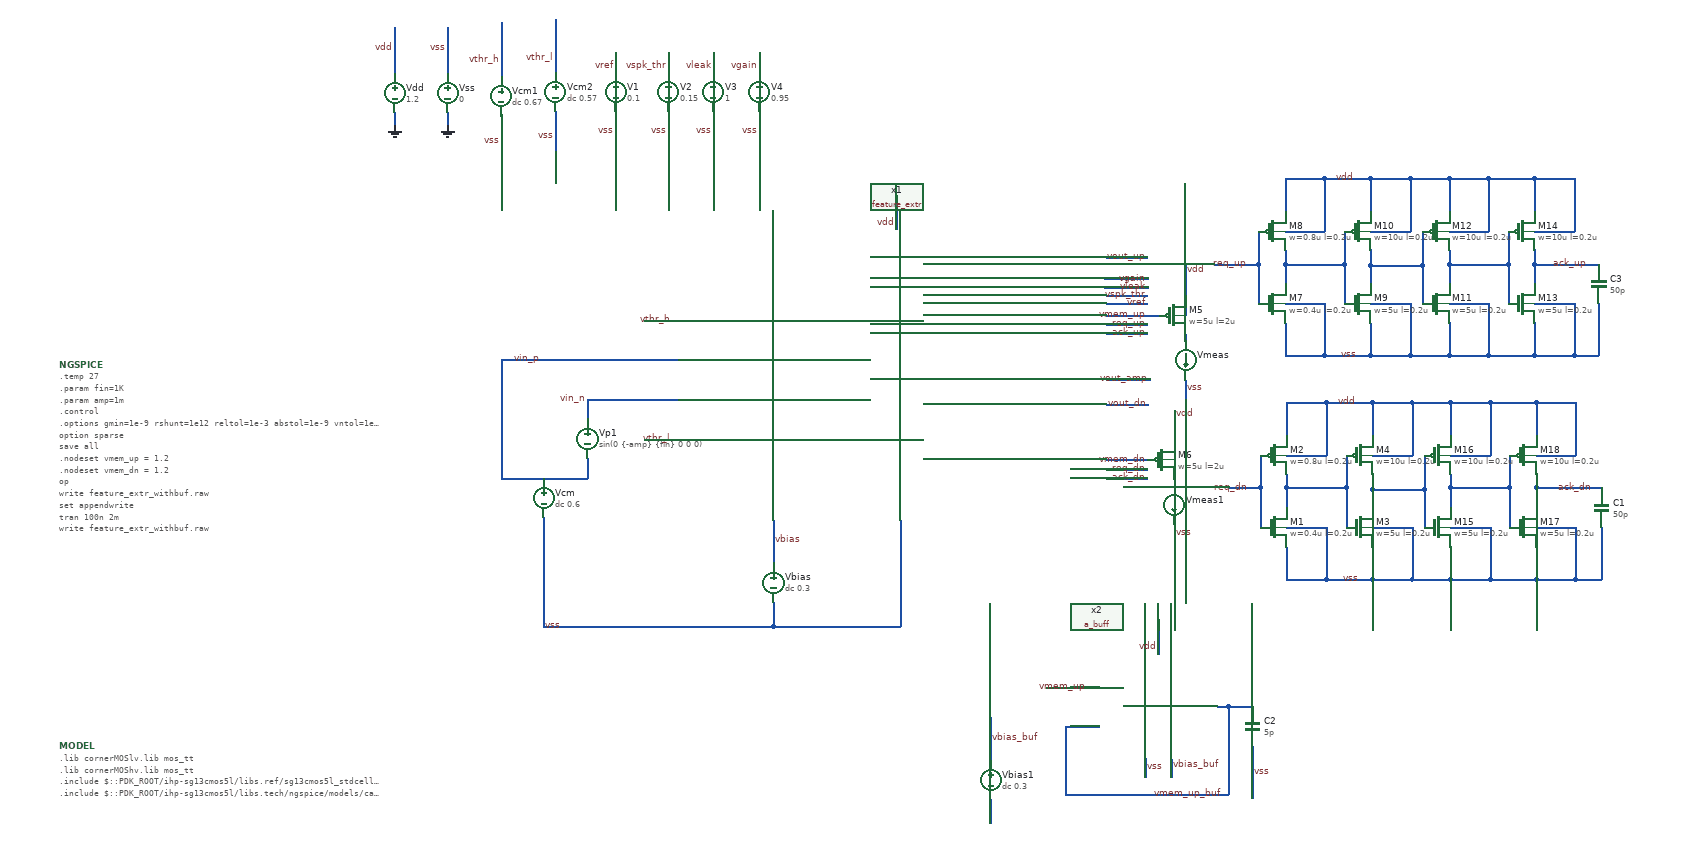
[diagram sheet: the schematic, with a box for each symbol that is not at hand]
v {xschem version=3.4.8RC file_version=1.3}
G {}
K {}
V {}
S {}
F {}
E {}
B 2 2471.25 -692.5 3271.25 -292.5 {flags=graph
y1=0.53
y2=0.74
ypos1=0
ypos2=2
divy=5
subdivy=1
unity=1
x1=0.0013195036
x2=0.0013233667
divx=5
subdivx=1
xlabmag=1.0
ylabmag=1.0
node="vout_amp
vthr_h
vthr_l
vthr
vint"
dataset=-1
unitx=1
logx=0
logy=0
rawfile=$netlist_dir/feature_extr.raw
sim_type=tran
autoload=1
color="3 7 4 12 9"}
B 2 3291.25 -1107.5 4091.25 -707.5 {flags=graph
y1=0.0013
y2=0.22
ypos1=0
ypos2=2
divy=5
subdivy=1
unity=1
x1=0.0013195036
x2=0.0013233667
divx=5
subdivx=1
xlabmag=1.0
ylabmag=1.0
node="vout_up
vout_dn"
dataset=-1
unitx=1
logx=0
logy=0
rawfile=$netlist_dir/feature_extr.raw
sim_type=tran
autoload=1
color="4 5"
hilight_wave=1}
B 2 3291.25 -692.5 4091.25 -292.5 {flags=graph
y1=1e-10
y2=2.5e-06
ypos1=0
ypos2=2
divy=5
subdivy=1
unity=1
x1=0.0013195036
x2=0.0013233667
divx=5
subdivx=1
xlabmag=1.0
ylabmag=1.0
dataset=-1
unitx=1
logx=0
logy=0
sim_type=tran
autoload=1
color="5 4"
node="i(v.x1.vmeas3)
i(v.x1.vmeas1)"
hilight_wave=1}
B 2 2481.25 -222.5 3281.25 177.5 {flags=graph
y1=0.53
y2=0.98
ypos1=0
ypos2=2
divy=5
subdivy=1
unity=1
x1=0.0013195036
x2=0.0013233667
divx=5
subdivx=1
xlabmag=1.0
ylabmag=1.0
dataset=-1
unitx=1
logx=0
logy=0
rawfile=$netlist_dir/feature_extr.raw
sim_type=tran
autoload=1
color="10 7 12"
node="vout_amp
x1.net6
x1.net5"}
B 2 3303.125 -267.5 4103.125 132.5 {flags=graph
y1=1.1e-09
y2=4.7e-08
ypos1=0
ypos2=2
divy=5
subdivy=1
unity=1
x1=0.0013195036
x2=0.0013233667
divx=5
subdivx=1
xlabmag=1.0
ylabmag=1.0
dataset=-1
unitx=1
logx=0
logy=0
sim_type=tran
autoload=1
color="4 6"
node="i(v.x1.vmeas4)
i(v.x1.vmeas2)"
hilight_wave=-1}
B 2 3330 196.25 4130 596.25 {flags=graph
y1=2.2e-09
y2=6.8e-08
ypos1=0
ypos2=2
divy=5
subdivy=1
unity=1
x1=0.0013195036
x2=0.0013233667
divx=5
subdivx=1
xlabmag=1.0
ylabmag=1.0
node=i(vmeas)
dataset=-1
unitx=1
logx=0
logy=0
rawfile=$netlist_dir/feature_extr.raw
sim_type=tran
autoload=1
color=4
hilight_wave=-1}
B 2 4170 196.25 4970 596.25 {flags=graph
y1=2.1e-09
y2=3.5e-08
ypos1=0
ypos2=2
divy=5
subdivy=1
unity=1
x1=0.0013195036
x2=0.0013233667
divx=5
subdivx=1
xlabmag=1.0
ylabmag=1.0
dataset=-1
unitx=1
logx=0
logy=0
rawfile=$netlist_dir/feature_extr.raw
sim_type=tran
autoload=1
color=4
node=i(vmeas1)
hilight_wave=-1}
B 2 4108.525390625 -695.302734375 4908.525390625 -295.302734375 {flags=graph
y1=-0.004
y2=1.3
ypos1=0
ypos2=2
divy=5
subdivy=1
unity=1
x1=0.0013195036
x2=0.0013233667
divx=5
subdivx=1
xlabmag=1.0
ylabmag=1.0
node="req_up
ack_up"
dataset=-1
unitx=1
logx=0
logy=0
rawfile=$netlist_dir/feature_extr.raw
sim_type=tran
autoload=1
color="5 4"
hcursor2_y=-0.86477319
hilight_wave=0}
B 2 2471.25 -1107.5 3271.25 -707.5 {flags=graph
y1=0.59
y2=0.61
ypos1=0
ypos2=2
divy=5
subdivy=1
unity=1
x1=0.0013195036
x2=0.0013233667
divx=5
subdivx=1
xlabmag=1.0
ylabmag=1.0
node="vin_p
vin_n"
dataset=-1
unitx=1
logx=0
logy=0
rawfile=$netlist_dir/feature_extr.raw
sim_type=tran
autoload=1
color="6 3"}
B 2 4108.2275390625 -1108.84765625 4908.2275390625 -708.84765625 {flags=graph
y1=0.94
y2=1.3
ypos1=0
ypos2=2
divy=5
subdivy=1
unity=1
x1=0.0013195036
x2=0.0013233667
divx=5
subdivx=1
xlabmag=1.0
ylabmag=1.0
node="vmem_up
vmem_dn"
dataset=-1
unitx=1
logx=0
logy=0
rawfile=$netlist_dir/feature_extr.raw
sim_type=tran
autoload=1
color="5 4"
hilight_wave=-1}
B 2 4928.2275390625 -1108.84765625 5728.2275390625 -708.84765625 {flags=graph
y1=0.959568
y2=1.558848
ypos1=0
ypos2=2
divy=5
subdivy=1
unity=1
x1=0.0013195036
x2=0.0013233667
divx=5
subdivx=1
xlabmag=1.0
ylabmag=1.0
dataset=-1
unitx=1
logx=0
logy=0
rawfile=$netlist_dir/feature_extr.raw
sim_type=tran
autoload=1
hilight_wave=1
color="5 4"
node="x1.x5.vmem_d
x1.x7.vmem_d"}
B 2 4108.525390625 -265.302734375 4908.525390625 134.697265625 {flags=graph
y1=-0.0036
y2=1.3
ypos1=0
ypos2=2
divy=5
subdivy=1
unity=1
x1=0.0013195036
x2=0.0013233667
divx=5
subdivx=1
xlabmag=1.0
ylabmag=1.0
node="req_dn
ack_dn"
dataset=-1
unitx=1
logx=0
logy=0
rawfile=$netlist_dir/feature_extr.raw
sim_type=tran
autoload=1
color="4 10"
hcursor2_y=-0.86477319
hilight_wave=-1}
B 2 1279.4775390625 14.90234375 2079.4775390625 414.90234375 {flags=graph
y1=0.94
y2=1.3
ypos1=0
ypos2=2
divy=5
subdivy=1
unity=1
x1=0.0013195036
x2=0.0013233667
divx=5
subdivx=1
xlabmag=1.0
ylabmag=1.0
node="vmem_up
vmem_up_buf"
dataset=-1
unitx=1
logx=0
logy=0
sim_type=tran
autoload=1
color="5 4"
hilight_wave=-1
rawfile=$netlist_dir/feature_extr_withbuf.raw}
N 510 -1102.5 510 -1082.5 {
lab=GND}
N 590 -1102.5 590 -1082.5 {
lab=GND}
N 672.5 -727.5 941.25 -727.5 {
lab=vin_p}
N 672.5 -727.5 672.5 -547.5 {lab=vin_p}
N 802.5 -577.5 802.5 -547.5 {lab=vin_p}
N 672.5 -547.5 802.5 -547.5 {lab=vin_p}
N 671.25 -1240 671.25 -1157.5 {lab=vthr_h}
N 671.25 -1100 671.25 -1040 {lab=vss}
N 753.75 -1103.75 753.75 -1043.75 {lab=vss}
N 510 -1232.5 510 -1162.5 {lab=vdd}
N 590 -1232.5 590 -1162.5 {lab=vss}
N 736.25 -487.5 736.25 -322.5 {lab=vss}
N 1277.5 -482.5 1277.5 -322.5 {lab=vss}
N 888.75 -787.5 941.25 -787.5 {lab=vthr_h}
N 888.75 -606.25 941.25 -606.25 {lab=vthr_l}
N 1272.5 -977.5 1272.5 -925 {lab=vdd}
N 1591.25 -882.5 1653.75 -882.5 {lab=vout_up}
N 1591.25 -697.5 1657.5 -697.5 {lab=vout_amp}
N 1591.25 -825 1653.75 -825 {lab=vspk_thr}
N 1591.25 -812.5 1653.75 -812.5 {lab=vref}
N 1591.25 -795 1671.25 -795 {lab=vmem_up}
N 1591.25 -781.25 1653.75 -781.25 {lab=req_up}
N 1591.25 -767.5 1653.75 -767.5 {lab=ack_up}
N 1591.25 -575 1653.75 -575 {lab=vmem_dn}
N 1591.25 -561.25 1653.75 -561.25 {lab=req_dn}
N 1591.25 -547.5 1653.75 -547.5 {lab=ack_dn}
N 2301.25 -733.75 2338.75 -733.75 {lab=vss}
N 2338.75 -812.5 2338.75 -733.75 {lab=vss}
N 1865 -532.5 1865 -502.5 {lab=#net1}
N 1825 -532.5 1825 -472.5 {lab=req_dn}
N 1865 -662.5 1865 -612.5 {lab=vdd}
N 1865 -472.5 1925 -472.5 {lab=vss}
N 1865 -582.5 1925 -582.5 {lab=vdd}
N 1925 -662.5 1925 -582.5 {lab=vdd}
N 1865 -662.5 1925 -662.5 {lab=vdd}
N 1865 -532.5 1955 -532.5 {lab=#net1}
N 1865 -552.5 1865 -532.5 {lab=#net1}
N 1955 -532.5 1955 -472.5 {lab=#net1}
N 1955 -582.5 1955 -532.5 {lab=#net1}
N 1995 -662.5 1995 -612.5 {lab=vdd}
N 1995 -472.5 2055 -472.5 {lab=vss}
N 1995 -582.5 2055 -582.5 {lab=vdd}
N 2055 -662.5 2055 -582.5 {lab=vdd}
N 1995 -662.5 2055 -662.5 {lab=vdd}
N 1925 -662.5 1995 -662.5 {lab=vdd}
N 1777.5 -532.5 1825 -532.5 {lab=req_dn}
N 1825 -582.5 1825 -532.5 {lab=req_dn}
N 2055 -472.5 2055 -393.75 {lab=vss}
N 1865 -442.5 1865 -393.75 {lab=vss}
N 1925 -472.5 1925 -393.75 {lab=vss}
N 1995 -442.5 1995 -393.75 {lab=vss}
N 2303.75 -393.75 2342.5 -393.75 {lab=vss}
N 1865 -393.75 1925 -393.75 {lab=vss}
N 1925 -393.75 1995 -393.75 {lab=vss}
N 1995 -393.75 2055 -393.75 {lab=vss}
N 2342.5 -472.5 2342.5 -393.75 {lab=vss}
N 753.75 -1243.75 753.75 -1163.75 {lab=vthr_l}
N 845.390625 -1194.296875 845.390625 -1164.296875 {lab=vref}
N 845.390625 -1104.296875 845.390625 -1064.296875 {lab=vss}
N 802.5 -667.5 802.5 -637.5 {lab=vin_n}
N 802.5 -667.5 941.25 -667.5 {lab=vin_n}
N 1591.25 -660 1655 -660 {lab=vout_dn}
N 1085 -322.5 1277.5 -322.5 {lab=vss}
N 1085 -483.75 1085 -418.75 {lab=vbias}
N 1085 -358.75 1085 -322.5 {lab=vss}
N 736.25 -322.5 1085 -322.5 {lab=vss}
N 1711.25 -870 1711.25 -795 {lab=vdd}
N 1693.75 -650 1693.75 -575 {lab=vdd}
N 1711.25 -766.25 1711.25 -755 {lab=#net2}
N 1711.25 -696.25 1711.25 -667.5 {lab=vss}
N 1693.75 -546.25 1693.75 -535 {lab=#net3}
N 1693.75 -476.25 1693.75 -447.5 {lab=vss}
N 925.390625 -1194.296875 925.390625 -1164.296875 {lab=vspk_thr}
N 925.390625 -1104.296875 925.390625 -1064.296875 {lab=vss}
N 993.515625 -1193.671875 993.515625 -1163.671875 {lab=vleak}
N 993.515625 -1103.671875 993.515625 -1063.671875 {lab=vss}
N 1588.4375 -837.5 1654.0625 -837.5 {lab=vleak}
N 1063.59375 -1194.375 1063.59375 -1164.375 {lab=vgain}
N 1063.59375 -1104.375 1063.59375 -1064.375 {lab=vss}
N 1588.4375 -850 1654.0625 -850 {lab=vgain}
N 1995 -530 1995 -499.921875 {lab=#net4}
N 2241.25 -872.5 2338.75 -872.5 {lab=ack_up}
N 2113.75 -532.5 2113.75 -502.5 {lab=#net5}
N 2113.75 -662.5 2113.75 -612.5 {lab=vdd}
N 2113.75 -472.5 2173.75 -472.5 {lab=vss}
N 2113.75 -582.5 2173.75 -582.5 {lab=vdd}
N 2173.75 -662.5 2173.75 -582.5 {lab=vdd}
N 2113.75 -532.5 2203.75 -532.5 {lab=#net5}
N 2113.75 -552.5 2113.75 -532.5 {lab=#net5}
N 2203.75 -532.5 2203.75 -472.5 {lab=#net5}
N 2203.75 -582.5 2203.75 -532.5 {lab=#net5}
N 2243.75 -662.5 2243.75 -612.5 {lab=vdd}
N 2243.75 -472.5 2303.75 -472.5 {lab=vss}
N 2243.75 -582.5 2303.75 -582.5 {lab=vdd}
N 2303.75 -662.5 2303.75 -582.5 {lab=vdd}
N 2243.75 -662.5 2303.75 -662.5 {lab=vdd}
N 2173.75 -662.5 2243.75 -662.5 {lab=vdd}
N 2113.75 -662.5 2173.75 -662.5 {lab=vdd}
N 2113.75 -443.75 2113.75 -393.75 {lab=vss}
N 2243.75 -443.75 2243.75 -393.75 {lab=vss}
N 2173.75 -393.75 2243.75 -393.75 {lab=vss}
N 2073.75 -530 2073.75 -472.5 {lab=#net4}
N 2173.75 -472.5 2173.75 -393.75 {lab=vss}
N 2113.75 -393.75 2173.75 -393.75 {lab=vss}
N 2303.75 -472.5 2303.75 -393.75 {lab=vss}
N 2243.75 -393.75 2303.75 -393.75 {lab=vss}
N 2243.75 -532.5 2243.75 -499.765625 {lab=ack_dn}
N 2055 -393.75 2113.75 -393.75 {lab=vss}
N 2055 -662.5 2113.75 -662.5 {lab=vdd}
N 1995 -530 2073.75 -530 {lab=#net4}
N 1995 -555.078125 1995 -530 {lab=#net4}
N 2073.75 -582.5 2073.75 -530 {lab=#net4}
N 2243.75 -532.5 2342.5 -532.5 {lab=ack_dn}
N 2243.75 -555.078125 2243.75 -532.5 {lab=ack_dn}
N 1862.5 -872.5 1862.5 -842.5 {lab=#net6}
N 1862.5 -1002.5 1862.5 -952.5 {lab=vdd}
N 1862.5 -812.5 1922.5 -812.5 {lab=vss}
N 1862.5 -922.5 1922.5 -922.5 {lab=vdd}
N 1922.5 -1002.5 1922.5 -922.5 {lab=vdd}
N 1862.5 -1002.5 1922.5 -1002.5 {lab=vdd}
N 1862.5 -872.5 1952.5 -872.5 {lab=#net6}
N 1862.5 -892.5 1862.5 -872.5 {lab=#net6}
N 1952.5 -872.5 1952.5 -812.5 {lab=#net6}
N 1952.5 -922.5 1952.5 -872.5 {lab=#net6}
N 1992.5 -1002.5 1992.5 -952.5 {lab=vdd}
N 1992.5 -812.5 2052.5 -812.5 {lab=vss}
N 1992.5 -922.5 2052.5 -922.5 {lab=vdd}
N 2052.5 -1002.5 2052.5 -922.5 {lab=vdd}
N 1992.5 -1002.5 2052.5 -1002.5 {lab=vdd}
N 1922.5 -1002.5 1992.5 -1002.5 {lab=vdd}
N 1822.5 -872.5 1822.5 -812.5 {lab=req_up}
N 2052.5 -812.5 2052.5 -733.75 {lab=vss}
N 1862.5 -782.5 1862.5 -733.75 {lab=vss}
N 1922.5 -812.5 1922.5 -733.75 {lab=vss}
N 1992.5 -782.5 1992.5 -733.75 {lab=vss}
N 1862.5 -733.75 1922.5 -733.75 {lab=vss}
N 1922.5 -733.75 1992.5 -733.75 {lab=vss}
N 1992.5 -733.75 2052.5 -733.75 {lab=vss}
N 1992.5 -870 1992.5 -839.921875 {lab=#net7}
N 2111.25 -872.5 2111.25 -842.5 {lab=#net8}
N 2111.25 -1002.5 2111.25 -952.5 {lab=vdd}
N 2111.25 -812.5 2171.25 -812.5 {lab=vss}
N 2111.25 -922.5 2171.25 -922.5 {lab=vdd}
N 2171.25 -1002.5 2171.25 -922.5 {lab=vdd}
N 2111.25 -872.5 2201.25 -872.5 {lab=#net8}
N 2111.25 -892.5 2111.25 -872.5 {lab=#net8}
N 2201.25 -872.5 2201.25 -812.5 {lab=#net8}
N 2201.25 -922.5 2201.25 -872.5 {lab=#net8}
N 2241.25 -1002.5 2241.25 -952.5 {lab=vdd}
N 2241.25 -812.5 2301.25 -812.5 {lab=vss}
N 2241.25 -922.5 2301.25 -922.5 {lab=vdd}
N 2301.25 -1002.5 2301.25 -922.5 {lab=vdd}
N 2241.25 -1002.5 2301.25 -1002.5 {lab=vdd}
N 2171.25 -1002.5 2241.25 -1002.5 {lab=vdd}
N 2111.25 -1002.5 2171.25 -1002.5 {lab=vdd}
N 2111.25 -783.75 2111.25 -733.75 {lab=vss}
N 2241.25 -783.75 2241.25 -733.75 {lab=vss}
N 2171.25 -733.75 2241.25 -733.75 {lab=vss}
N 2071.25 -870 2071.25 -812.5 {lab=#net7}
N 2171.25 -812.5 2171.25 -733.75 {lab=vss}
N 2111.25 -733.75 2171.25 -733.75 {lab=vss}
N 2301.25 -812.5 2301.25 -733.75 {lab=vss}
N 2241.25 -733.75 2301.25 -733.75 {lab=vss}
N 2052.5 -733.75 2111.25 -733.75 {lab=vss}
N 2052.5 -1002.5 2111.25 -1002.5 {lab=vdd}
N 1992.5 -870 2071.25 -870 {lab=#net7}
N 1992.5 -895.078125 1992.5 -870 {lab=#net7}
N 2071.25 -922.5 2071.25 -870 {lab=#net7}
N 2241.25 -872.5 2241.25 -839.765625 {lab=ack_up}
N 2241.25 -895.078125 2241.25 -872.5 {lab=ack_up}
N 1755 -872.5 1822.5 -872.5 {lab=req_up}
N 1822.5 -922.5 1822.5 -872.5 {lab=req_up}
N 1670 -332.5 1670 -280 {lab=vdd}
N 1650 -121.25 1650 -92.5 {lab=vss}
N 1528.75 -170 1580 -170 {lab=vmem_up_buf}
N 1528.75 -170 1528.75 -67.5 {lab=vmem_up_buf}
N 1776.25 -200 1776.25 -67.5 {lab=vmem_up_buf}
N 1528.75 -67.5 1776.25 -67.5 {lab=vmem_up_buf}
N 1500 -230 1580 -230 {lab=vmem_up}
N 1690 -120 1690 -92.5 {lab=vbias_buf}
N 1812.5 -140 1812.5 -61.25 {lab=vss}
N 1776.25 -200 1812.5 -200 {lab=vmem_up_buf}
N 1760 -200 1776.25 -200 {lab=vmem_up_buf}
N 1415 -183.75 1415 -118.75 {lab=vbias_buf}
N 1415 -58.75 1415 -22.5 {lab=#net9}
C {devices/vsource.sym} 510 -1132.5 0 0 {name=Vdd value=1.2}
C {devices/gnd.sym} 510 -1082.5 0 0 {name=l3 lab=GND}
C {devices/launcher.sym} 560 -140 0 0 {name=h2
descr="simulate" 
tclcommand="xschem save; xschem netlist; xschem simulate"
}
C {devices/launcher.sym} 800 -140 0 0 {name=h3
descr="annotate OP" 
tclcommand="set show_hidden_texts 1; xschem annotate_op"
}
C {devices/vsource.sym} 590 -1132.5 0 0 {name=Vss value=0}
C {devices/gnd.sym} 590 -1082.5 0 0 {name=l1 lab=GND}
C {devices/vsource.sym} 736.25 -517.5 0 0 {name=Vcm value="dc 0.6"}
C {devices/lab_wire.sym} 732.5 -727.5 0 0 {name=p4 sig_type=std_logic lab=vin_p}
C {devices/lab_wire.sym} 802.5 -667.5 0 0 {name=p7 sig_type=std_logic lab=vin_n}
C {devices/vsource.sym} 802.5 -607.5 0 0 {name=Vp1 value="sin(0 \{-amp\} \{fin\} 0 0 0)"}
C {devices/code_shown.sym} 0 -720 0 0 {name=NGSPICE only_toplevel=true 
value="
.temp 27
.param fin=1K
.param amp=1m
.control
.options gmin=1e-9 rshunt=1e12 reltol=1e-3 abstol=1e-9 vntol=1e-6

option sparse
save all

.nodeset vmem_up = 1.2
.nodeset vmem_dn = 1.2
op
write feature_extr_withbuf.raw
set appendwrite

tran 100n 2m
write feature_extr_withbuf.raw
*wrdata amplification.csv vin_p vin_n vout_amp
*wrdata comparison.csv vout_up vout_dn vthr_h vthr_l i(v.x1.vmeas1) i(v.x1.vmeas3)
*wrdata event_conversion.csv req_up req_dn vmem_up vmem_dn


plot v(req_up) v(req_dn)
plot v(vmem_up) v(vmem_dn)


.endc
"}
C {devices/code_shown.sym} 0 -140 0 0 {name=MODEL only_toplevel=true
format="tcleval( @value )"
value="
.lib cornerMOSlv.lib mos_tt
.lib cornerMOShv.lib mos_tt
.include $::PDK_ROOT/ihp-sg13cmos5l/libs.ref/sg13cmos5l_stdcell/spice/sg13cmos5l_stdcell.spice
.include $::PDK_ROOT/ihp-sg13cmos5l/libs.tech/ngspice/models/cap_mfringe.lib
"}
C {devices/title.sym} 160 0 0 0 {name=l5 author="(c) 2024-2025 Harald Pretl, Apache-2.0 license"}
C {devices/vsource.sym} 671.25 -1127.5 0 0 {name=Vcm1 value="dc 0.67"}
C {devices/vsource.sym} 753.75 -1133.75 0 0 {name=Vcm2 value="dc 0.57"}
C {devices/lab_wire.sym} 1806.25 -872.5 0 0 {name=p32 sig_type=std_logic lab=req_up}
C {capa.sym} 2338.75 -842.5 0 0 {name=C3
m=1
value=50p
footprint=1206
device="ceramic capacitor"}
C {lab_wire.sym} 931.25 -787.5 0 0 {name=p6 sig_type=std_logic lab=vthr_h}
C {lab_wire.sym} 931.25 -606.25 0 0 {name=p8 sig_type=std_logic lab=vthr_l}
C {lab_wire.sym} 1272.5 -935 1 0 {name=p9 sig_type=std_logic lab=vdd}
C {lab_wire.sym} 1652.5 -882.5 0 0 {name=p11 sig_type=std_logic lab=vout_up}
C {lab_wire.sym} 1656.25 -697.5 0 0 {name=p12 sig_type=std_logic lab=vout_amp}
C {lab_wire.sym} 1655 -660 0 0 {name=p13 sig_type=std_logic lab=vout_dn}
C {lab_wire.sym} 1653.75 -825 0 0 {name=p16 sig_type=std_logic lab=vspk_thr}
C {lab_wire.sym} 1653.75 -812.5 0 0 {name=p19 sig_type=std_logic lab=vref}
C {lab_wire.sym} 1652.5 -781.25 0 0 {name=p20 sig_type=std_logic lab=req_up}
C {lab_wire.sym} 1653.75 -795 0 0 {name=p22 sig_type=std_logic lab=vmem_up}
C {lab_wire.sym} 1652.5 -767.5 0 0 {name=p23 sig_type=std_logic lab=ack_up}
C {lab_wire.sym} 1652.5 -561.25 0 0 {name=p24 sig_type=std_logic lab=req_dn}
C {lab_wire.sym} 1653.75 -575 0 0 {name=p25 sig_type=std_logic lab=vmem_dn}
C {lab_wire.sym} 1652.5 -547.5 0 0 {name=p26 sig_type=std_logic lab=ack_dn}
C {sg13g2_pr/sg13_lv_nmos.sym} 1845 -472.5 0 0 {name=M1
l=0.2u
w=0.4u
ng=1
m=1
model=sg13_lv_nmos
spiceprefix=X
}
C {sg13g2_pr/sg13_lv_pmos.sym} 1845 -582.5 0 0 {name=M2
l=0.2u
w=0.8u
ng=1
m=1
model=sg13_lv_pmos
spiceprefix=X
}
C {sg13g2_pr/sg13_lv_nmos.sym} 1975 -472.5 0 0 {name=M3
l=0.2u
w=5u
ng=1
m=1
model=sg13_lv_nmos
spiceprefix=X
}
C {sg13g2_pr/sg13_lv_pmos.sym} 1975 -582.5 0 0 {name=M4
l=0.2u
w=10u
ng=1
m=1
model=sg13_lv_pmos
spiceprefix=X
}
C {devices/lab_wire.sym} 1807.5 -532.5 0 0 {name=p29 sig_type=std_logic lab=req_dn}
C {capa.sym} 2342.5 -502.5 0 0 {name=C1
m=1
value=50p
footprint=1206
device="ceramic capacitor"}
C {vsource.sym} 845.390625 -1134.296875 0 0 {name=V1 value=0.1 savecurrent=false}
C {devices/lab_wire.sym} 845.390625 -1173.046875 1 0 {name=p36 sig_type=std_logic lab=vref}
C {noconn.sym} 1652.5 -882.5 2 0 {name=l2}
C {noconn.sym} 1656.25 -697.5 2 0 {name=l6}
C {noconn.sym} 1655 -660 2 0 {name=l7}
C {devices/vsource.sym} 1085 -388.75 0 0 {name=Vbias value="dc 0.3"}
C {lab_wire.sym} 510 -1200 1 0 {name=p1 sig_type=std_logic lab=vdd}
C {lab_wire.sym} 590 -1200 1 0 {name=p2 sig_type=std_logic lab=vss}
C {lab_wire.sym} 671.25 -1058.75 1 0 {name=p5 sig_type=std_logic lab=vss}
C {lab_wire.sym} 753.75 -1067.5 1 0 {name=p17 sig_type=std_logic lab=vss}
C {lab_wire.sym} 671.25 -1182.5 1 0 {name=p18 sig_type=std_logic lab=vthr_h}
C {lab_wire.sym} 753.75 -1185 1 0 {name=p10 sig_type=std_logic lab=vthr_l}
C {lab_wire.sym} 736.25 -322.5 2 0 {name=p21 sig_type=std_logic lab=vss}
C {lab_wire.sym} 1940 -662.5 2 0 {name=p27 sig_type=std_logic lab=vdd}
C {lab_wire.sym} 1947.5 -393.75 2 0 {name=p31 sig_type=std_logic lab=vss}
C {lab_wire.sym} 845.390625 -1074.296875 1 0 {name=p38 sig_type=std_logic lab=vss}
C {sg13cmos5l_pr/sg13_lv_pmos.sym} 1691.25 -795 0 0 {name=M5
l=2u
w=5u
ng=4
m=2
model=sg13_lv_pmos
spiceprefix=X
}
C {sg13cmos5l_pr/sg13_lv_pmos.sym} 1673.75 -575 0 0 {name=M6
l=2u
w=5u
ng=4
m=2
model=sg13_lv_pmos
spiceprefix=X
}
C {lab_wire.sym} 1711.25 -863.75 2 0 {name=p39 sig_type=std_logic lab=vdd}
C {lab_wire.sym} 1693.75 -645 2 0 {name=p41 sig_type=std_logic lab=vdd}
C {ammeter.sym} 1711.25 -726.25 0 0 {name=Vmeas savecurrent=true spice_ignore=0}
C {lab_wire.sym} 1711.25 -683.75 2 0 {name=p42 sig_type=std_logic lab=vss}
C {ammeter.sym} 1693.75 -506.25 0 0 {name=Vmeas1 savecurrent=true spice_ignore=0}
C {lab_wire.sym} 1693.75 -463.75 2 0 {name=p43 sig_type=std_logic lab=vss}
C {vsource.sym} 925.390625 -1134.296875 0 0 {name=V2 value=0.15 avecurrent=false}
C {devices/lab_wire.sym} 925.390625 -1173.046875 1 0 {name=p44 sig_type=std_logic lab=vspk_thr}
C {lab_wire.sym} 925.390625 -1074.296875 1 0 {name=p45 sig_type=std_logic lab=vss}
C {vsource.sym} 993.515625 -1133.671875 0 0 {name=V3 value=1 savecurrent=false}
C {devices/lab_wire.sym} 993.515625 -1172.421875 1 0 {name=p40 sig_type=std_logic lab=vleak}
C {lab_wire.sym} 993.515625 -1073.671875 1 0 {name=p46 sig_type=std_logic lab=vss}
C {feature_extr.sym} 1240 -700 0 0 {name=x1}
C {lab_wire.sym} 1653.125 -837.5 0 0 {name=p15 sig_type=std_logic lab=vleak}
C {vsource.sym} 1063.59375 -1134.375 0 0 {name=V4 value=0.95 savecurrent=false}
C {devices/lab_wire.sym} 1063.59375 -1173.125 1 0 {name=p33 sig_type=std_logic lab=vgain}
C {lab_wire.sym} 1063.59375 -1074.375 1 0 {name=p34 sig_type=std_logic lab=vss}
C {lab_wire.sym} 1653.125 -850 0 0 {name=p35 sig_type=std_logic lab=vgain}
C {sg13g2_pr/sg13_lv_nmos.sym} 2093.75 -472.5 0 0 {name=M15
l=0.2u
w=5u
ng=1
m=1
model=sg13_lv_nmos
spiceprefix=X
}
C {sg13g2_pr/sg13_lv_pmos.sym} 2093.75 -582.5 0 0 {name=M16
l=0.2u
w=10u
ng=1
m=1
model=sg13_lv_pmos
spiceprefix=X
}
C {sg13g2_pr/sg13_lv_nmos.sym} 2223.75 -472.5 0 0 {name=M17
l=0.2u
w=5u
ng=1
m=1
model=sg13_lv_nmos
spiceprefix=X
}
C {sg13g2_pr/sg13_lv_pmos.sym} 2223.75 -582.5 0 0 {name=M18
l=0.2u
w=10u
ng=1
m=1
model=sg13_lv_pmos
spiceprefix=X
}
C {lab_wire.sym} 2331.25 -532.5 0 0 {name=p37 sig_type=std_logic lab=ack_dn}
C {lab_wire.sym} 2322.5 -872.5 0 0 {name=p47 sig_type=std_logic lab=ack_up}
C {sg13g2_pr/sg13_lv_nmos.sym} 1842.5 -812.5 0 0 {name=M7
l=0.2u
w=0.4u
ng=1
m=1
model=sg13_lv_nmos
spiceprefix=X
}
C {sg13g2_pr/sg13_lv_pmos.sym} 1842.5 -922.5 0 0 {name=M8
l=0.2u
w=0.8u
ng=1
m=1
model=sg13_lv_pmos
spiceprefix=X
}
C {sg13g2_pr/sg13_lv_nmos.sym} 1972.5 -812.5 0 0 {name=M9
l=0.2u
w=5u
ng=1
m=1
model=sg13_lv_nmos
spiceprefix=X
}
C {sg13g2_pr/sg13_lv_pmos.sym} 1972.5 -922.5 0 0 {name=M10
l=0.2u
w=10u
ng=1
m=1
model=sg13_lv_pmos
spiceprefix=X
}
C {lab_wire.sym} 1937.5 -1002.5 2 0 {name=p3 sig_type=std_logic lab=vdd}
C {lab_wire.sym} 1945 -733.75 2 0 {name=p14 sig_type=std_logic lab=vss}
C {sg13g2_pr/sg13_lv_nmos.sym} 2091.25 -812.5 0 0 {name=M11
l=0.2u
w=5u
ng=1
m=1
model=sg13_lv_nmos
spiceprefix=X
}
C {sg13g2_pr/sg13_lv_pmos.sym} 2091.25 -922.5 0 0 {name=M12
l=0.2u
w=10u
ng=1
m=1
model=sg13_lv_pmos
spiceprefix=X
}
C {sg13g2_pr/sg13_lv_nmos.sym} 2221.25 -812.5 0 0 {name=M13
l=0.2u
w=5u
ng=1
m=1
model=sg13_lv_nmos
spiceprefix=X
}
C {sg13g2_pr/sg13_lv_pmos.sym} 2221.25 -922.5 0 0 {name=M14
l=0.2u
w=10u
ng=1
m=1
model=sg13_lv_pmos
spiceprefix=X
}
C {a_buff.sym} 1650 -200 0 0 {name=x2}
C {lab_wire.sym} 1670 -290 1 0 {name=p28 sig_type=std_logic lab=vdd}
C {lab_wire.sym} 1650 -108.75 2 0 {name=p30 sig_type=std_logic lab=vss}
C {lab_wire.sym} 1085 -452.5 2 0 {name=p48 sig_type=std_logic lab=vbias}
C {lab_wire.sym} 1690 -111.25 2 0 {name=p49 sig_type=std_logic lab=vbias_buf}
C {lab_wire.sym} 1562.5 -230 0 0 {name=p50 sig_type=std_logic lab=vmem_up}
C {lab_wire.sym} 1767.5 -67.5 0 0 {name=p51 sig_type=std_logic lab=vmem_up_buf}
C {capa.sym} 1812.5 -170 0 0 {name=C2
m=1
value=5p
footprint=1206
device="ceramic capacitor"}
C {lab_wire.sym} 1812.5 -100 2 0 {name=p52 sig_type=std_logic lab=vss}
C {devices/vsource.sym} 1415 -88.75 0 0 {name=Vbias1 value="dc 0.3"}
C {lab_wire.sym} 1415 -152.5 2 0 {name=p53 sig_type=std_logic lab=vbias_buf}
